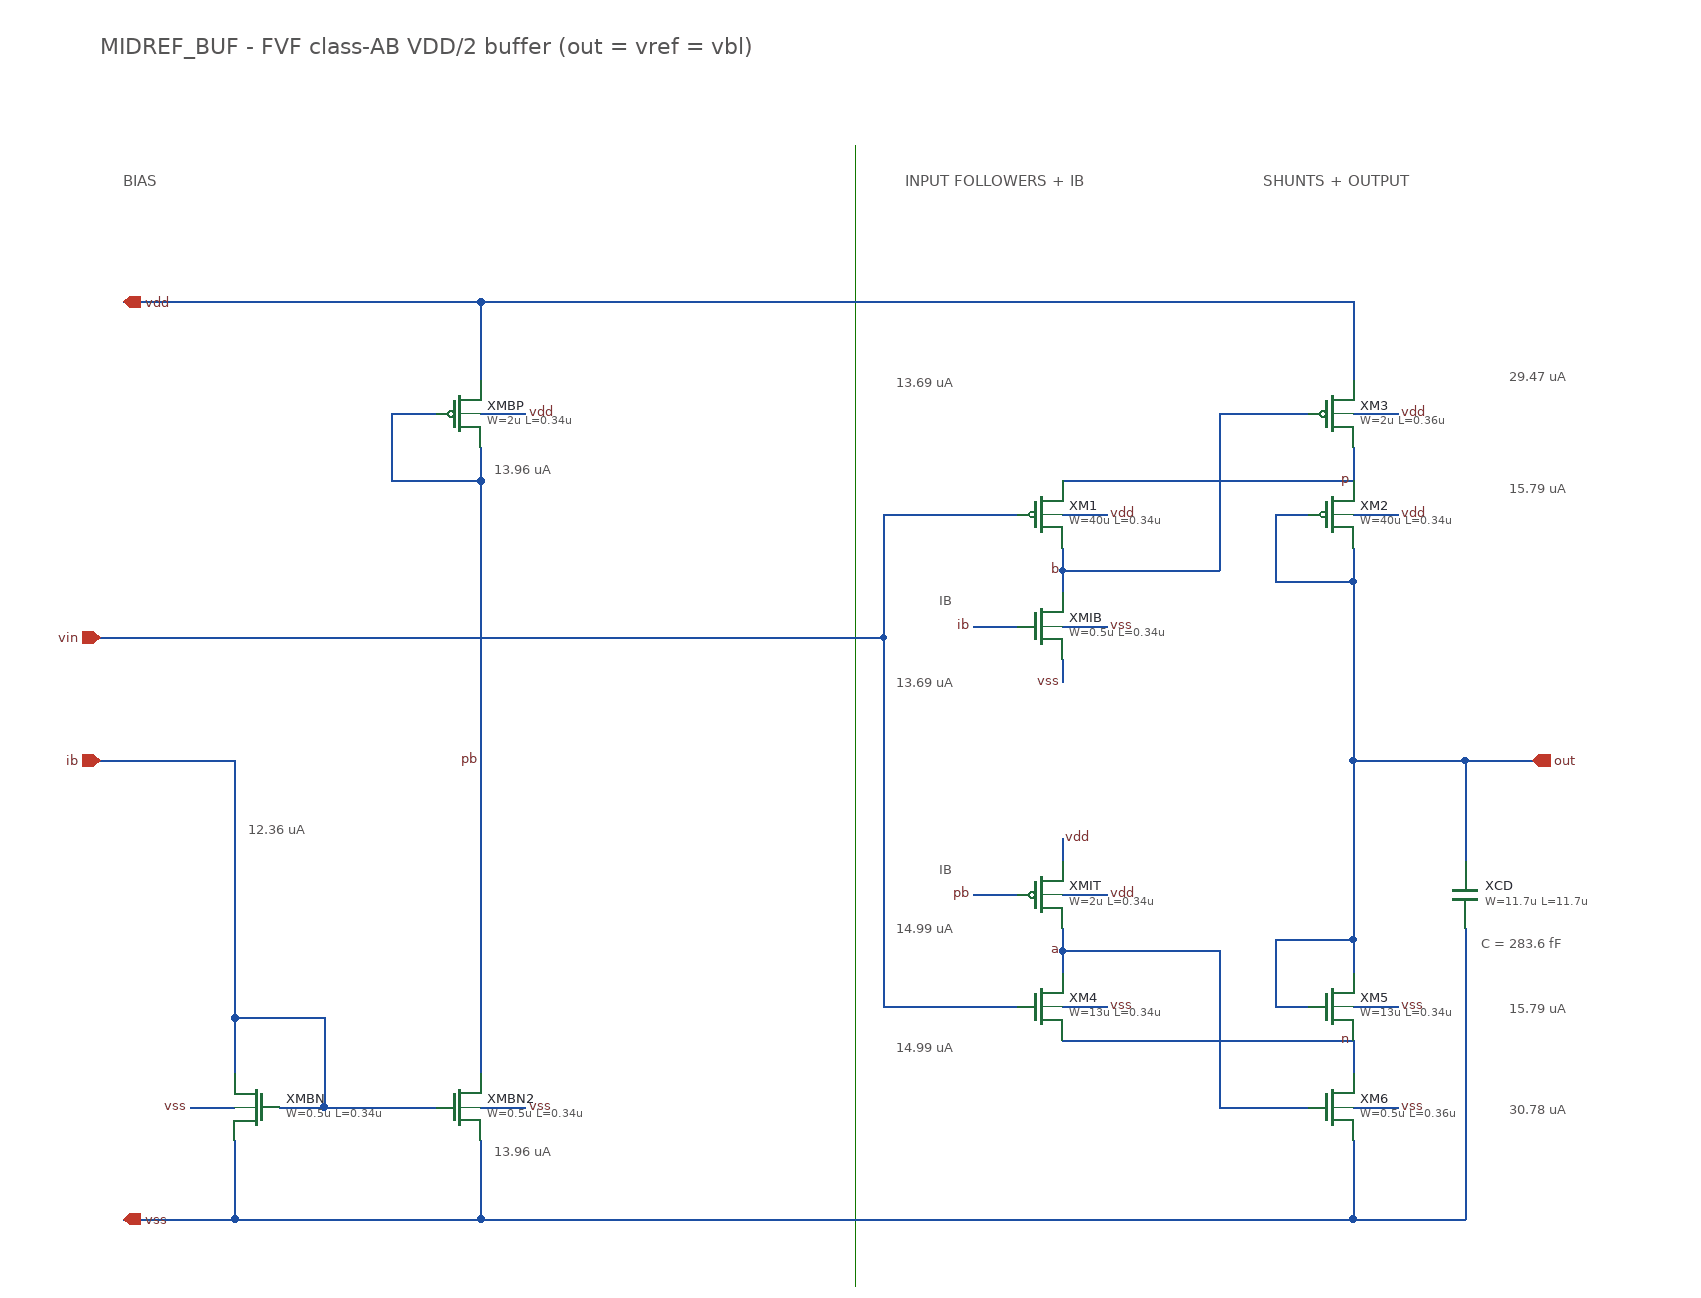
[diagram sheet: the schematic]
v {xschem version=3.4.8RC file_version=1.2}
G {}
K {}
V {}
S {}
E {}
T {MIDREF_BUF  -  FVF class-AB VDD/2 buffer (out = vref = vbl)} 40 -1100 0 0 0.6 0.6 {}
T {12.36 uA} 172 -400 0 0 0.36 0.36 {layer=4}
T {13.96 uA} 392 -112 0 0 0.36 0.36 {layer=4}
T {13.96 uA} 392 -722 0 0 0.36 0.36 {layer=4}
T {13.69 uA} 752 -800 0 0 0.36 0.36 {layer=4}
T {13.69 uA} 752 -532 0 0 0.36 0.36 {layer=4}
T {14.99 uA} 752 -312 0 0 0.36 0.36 {layer=4}
T {14.99 uA} 752 -205 0 0 0.36 0.36 {layer=4}
T {29.47 uA} 1300 -805 0 0 0.36 0.36 {layer=4}
T {15.79 uA} 1300 -705 0 0 0.36 0.36 {layer=4}
T {15.79 uA} 1300 -240 0 0 0.36 0.36 {layer=4}
T {30.78 uA} 1300 -150 0 0 0.36 0.36 {layer=4}
T {C = 283.6 fF} 1275 -298 0 0 0.36 0.36 {layer=4}
T {BIAS} 60 -980 0 0 0.4 0.4 {}
T {INPUT FOLLOWERS + IB} 760 -980 0 0 0.4 0.4 {}
T {SHUNTS + OUTPUT} 1080 -980 0 0 0.4 0.4 {}
T {IB} 790 -605 0 0 0.35 0.35 {layer=8}
T {IB} 790 -365 0 0 0.35 0.35 {layer=8}
L 4 715 -1000 715 20 {dash=6}
N 40 -450 160 -450 {lab=ib}
N 160 -450 160 -220 {lab=ib}
N 160 -220 160 -170 {lab=ib}
N 160 -220 240 -220 {lab=ib}
N 240 -220 240 -140 {lab=ib}
N 200 -140 240 -140 {lab=ib}
N 240 -140 340 -140 {lab=ib}
N 160 -110 160 -40 {lab=vss}
N 380 -110 380 -40 {lab=vss}
N 380 -730 380 -700 {lab=pb}
N 380 -700 380 -450 {lab=pb}
N 380 -450 380 -170 {lab=pb}
N 300 -760 340 -760 {lab=pb}
N 300 -760 300 -700 {lab=pb}
N 300 -700 380 -700 {lab=pb}
N 380 -860 380 -790 {lab=vdd}
N 120 -140 160 -140 {lab=vss}
N 380 -140 420 -140 {lab=vss}
N 380 -760 420 -760 {lab=vdd}
N 40 -560 740 -560 {lab=vin}
N 740 -670 740 -560 {lab=vin}
N 740 -560 740 -230 {lab=vin}
N 740 -670 860 -670 {lab=vin}
N 740 -230 860 -230 {lab=vin}
N 900 -640 900 -620 {lab=b}
N 900 -620 900 -600 {lab=b}
N 900 -540 900 -520 {lab=vss}
N 900 -300 900 -280 {lab=a}
N 900 -280 900 -260 {lab=a}
N 900 -380 900 -360 {lab=vdd}
N 820 -570 860 -570 {lab=ib}
N 820 -330 860 -330 {lab=pb}
N 900 -620 1040 -620 {lab=b}
N 1040 -760 1040 -620 {lab=b}
N 1040 -760 1120 -760 {lab=b}
N 900 -280 1040 -280 {lab=a}
N 1040 -280 1040 -140 {lab=a}
N 1040 -140 1120 -140 {lab=a}
N 900 -700 1160 -700 {lab=p}
N 1160 -730 1160 -700 {lab=p}
N 900 -200 1160 -200 {lab=n}
N 1160 -200 1160 -170 {lab=n}
N 1160 -860 1160 -790 {lab=vdd}
N 1160 -110 1160 -40 {lab=vss}
N 1160 -640 1160 -610 {lab=out}
N 1160 -610 1160 -450 {lab=out}
N 1160 -450 1160 -290 {lab=out}
N 1160 -290 1160 -260 {lab=out}
N 1090 -610 1160 -610 {lab=out}
N 1090 -670 1090 -610 {lab=out}
N 1090 -670 1120 -670 {lab=out}
N 1090 -290 1160 -290 {lab=out}
N 1090 -290 1090 -230 {lab=out}
N 1090 -230 1120 -230 {lab=out}
N 1160 -450 1260 -450 {lab=out}
N 1260 -450 1320 -450 {lab=out}
N 1260 -450 1260 -360 {lab=out}
N 1260 -300 1260 -40 {lab=vss}
N 900 -670 940 -670 {lab=vdd}
N 900 -570 940 -570 {lab=vss}
N 900 -330 940 -330 {lab=vdd}
N 900 -230 940 -230 {lab=vss}
N 1160 -760 1200 -760 {lab=vdd}
N 1160 -670 1200 -670 {lab=vdd}
N 1160 -230 1200 -230 {lab=vss}
N 1160 -140 1200 -140 {lab=vss}
N 60 -860 380 -860 {lab=vdd}
N 380 -860 1160 -860 {lab=vdd}
N 60 -40 160 -40 {lab=vss}
N 160 -40 380 -40 {lab=vss}
N 380 -40 1160 -40 {lab=vss}
N 1160 -40 1260 -40 {lab=vss}
C {devices/iopin.sym} 60 -860 0 1 {name=pvdd lab=vdd sim_pinnumber=4}
C {devices/iopin.sym} 60 -40 0 1 {name=pvss lab=vss sim_pinnumber=5}
C {devices/ipin.sym} 40 -450 0 0 {name=pib lab=ib sim_pinnumber=3}
C {devices/ipin.sym} 40 -560 0 0 {name=pvin lab=vin sim_pinnumber=2}
C {devices/opin.sym} 1320 -450 0 0 {name=pout lab=out sim_pinnumber=1}
C {devices/lab_pin.sym} 120 -140 0 0 {name=l1 sig_type=std_logic lab=vss}
C {devices/lab_pin.sym} 420 -140 0 1 {name=l2 sig_type=std_logic lab=vss}
C {devices/lab_pin.sym} 420 -760 0 1 {name=l3 sig_type=std_logic lab=vdd}
C {devices/lab_wire.sym} 380 -450 0 0 {name=l4 sig_type=std_logic lab=pb}
C {devices/lab_pin.sym} 900 -520 0 0 {name=l5 sig_type=std_logic lab=vss}
C {devices/lab_pin.sym} 900 -380 0 1 {name=l6 sig_type=std_logic lab=vdd}
C {devices/lab_pin.sym} 820 -570 0 0 {name=l7 sig_type=std_logic lab=ib}
C {devices/lab_pin.sym} 820 -330 0 0 {name=l8 sig_type=std_logic lab=pb}
C {devices/lab_pin.sym} 940 -670 0 1 {name=l9 sig_type=std_logic lab=vdd}
C {devices/lab_pin.sym} 940 -570 0 1 {name=l10 sig_type=std_logic lab=vss}
C {devices/lab_pin.sym} 940 -330 0 1 {name=l11 sig_type=std_logic lab=vdd}
C {devices/lab_pin.sym} 940 -230 0 1 {name=l12 sig_type=std_logic lab=vss}
C {devices/lab_pin.sym} 1200 -760 0 1 {name=l13 sig_type=std_logic lab=vdd}
C {devices/lab_pin.sym} 1200 -670 0 1 {name=l14 sig_type=std_logic lab=vdd}
C {devices/lab_pin.sym} 1200 -230 0 1 {name=l15 sig_type=std_logic lab=vss}
C {devices/lab_pin.sym} 1200 -140 0 1 {name=l16 sig_type=std_logic lab=vss}
C {devices/lab_wire.sym} 900 -620 0 0 {name=l17 sig_type=std_logic lab=b}
C {devices/lab_wire.sym} 900 -280 0 0 {name=l18 sig_type=std_logic lab=a}
C {devices/lab_wire.sym} 1160 -700 0 0 {name=l19 sig_type=std_logic lab=p}
C {devices/lab_wire.sym} 1160 -200 0 0 {name=l20 sig_type=std_logic lab=n}
C {symbols/nfet_03v3.sym} 180 -140 0 1 {name=XMBN
L=0.34u
W=0.5u
nf=1
m=1
model=nfet_03v3
spiceprefix=""
format="@name @pinlist @model L=@L W=@W nf=@nf m=@m"}
C {symbols/nfet_03v3.sym} 360 -140 0 0 {name=XMBN2
L=0.34u
W=0.5u
nf=1
m=1
model=nfet_03v3
spiceprefix=""
format="@name @pinlist @model L=@L W=@W nf=@nf m=@m"}
C {symbols/pfet_03v3.sym} 360 -760 0 0 {name=XMBP
L=0.34u
W=2u
nf=1
m=1
model=pfet_03v3
spiceprefix=""
format="@name @pinlist @model L=@L W=@W nf=@nf m=@m"}
C {symbols/pfet_03v3.sym} 880 -330 0 0 {name=XMIT
L=0.34u
W=2u
nf=1
m=1
model=pfet_03v3
spiceprefix=""
format="@name @pinlist @model L=@L W=@W nf=@nf m=@m"}
C {symbols/nfet_03v3.sym} 880 -570 0 0 {name=XMIB
L=0.34u
W=0.5u
nf=1
m=1
model=nfet_03v3
spiceprefix=""
format="@name @pinlist @model L=@L W=@W nf=@nf m=@m"}
C {symbols/pfet_03v3.sym} 1140 -760 0 0 {name=XM3
L=0.36u
W=2u
nf=1
m=1
model=pfet_03v3
spiceprefix=""
format="@name @pinlist @model L=@L W=@W nf=@nf m=@m"}
C {symbols/pfet_03v3.sym} 880 -670 0 0 {name=XM1
L=0.34u
W=40u
nf=20
m=1
model=pfet_03v3
spiceprefix=""
format="@name @pinlist @model L=@L W=@W nf=@nf m=@m"}
C {symbols/pfet_03v3.sym} 1140 -670 0 0 {name=XM2
L=0.34u
W=40u
nf=20
m=1
model=pfet_03v3
spiceprefix=""
format="@name @pinlist @model L=@L W=@W nf=@nf m=@m"}
C {symbols/nfet_03v3.sym} 1140 -140 0 0 {name=XM6
L=0.36u
W=0.5u
nf=1
m=1
model=nfet_03v3
spiceprefix=""
format="@name @pinlist @model L=@L W=@W nf=@nf m=@m"}
C {symbols/nfet_03v3.sym} 880 -230 0 0 {name=XM4
L=0.34u
W=13u
nf=26
m=1
model=nfet_03v3
spiceprefix=""
format="@name @pinlist @model L=@L W=@W nf=@nf m=@m"}
C {symbols/nfet_03v3.sym} 1140 -230 0 0 {name=XM5
L=0.34u
W=13u
nf=26
m=1
model=nfet_03v3
spiceprefix=""
format="@name @pinlist @model L=@L W=@W nf=@nf m=@m"}
C {symbols/cap_mim_2f0fF.sym} 1260 -330 0 0 {name=XCD W=11.7u L=11.7u model=cap_mim_2f0_m4m5_noshield spiceprefix="" m=1}
C {devices/title.sym} 0 140 0 0 {name=l99 author="ASIC R&D - mixed_signal/midrail_ref - midref_buf"}
